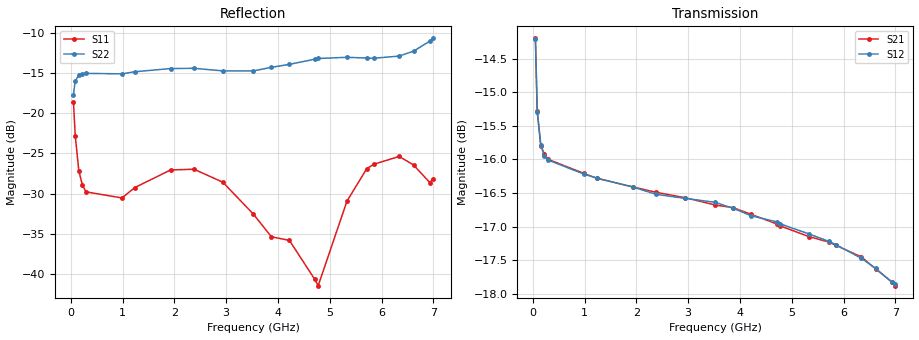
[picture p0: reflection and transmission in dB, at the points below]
! Integrated Device Technology
! Corporate Headquarters
! 6024 Silver Creek Valley Road
! San Jose, CA 95138  USA
! Phone:  1-408-284-8200
! Toll Free:  1-800-223-1366
! Webpage:  http://www.idt.com/
! Timing and RF Division
! 515 Groton Road, Suite 102
! Westford, MA 01886-6024
! Device:  F2258
! Description: Voltage Variable RF Attenuator
! Frequency:  50.0 -  6000.00 MHz
! Package:  3x3 mm Thin QFN Plastic Package: 16 pin
! Ports:  2 RF, 2 DC
!  Pin  1  = NC
!  Pin  2  = NC
!  Pin  3  = RF2  = Port 2
!  Pin  4  = GND
!  Pin  5  = Vdd
!  Pin  6  = NC
!  Pin  7  = VCTRL
!  Pin  8  = NC
!  Pin  9  = GND
!  Pin 10  = RF1  = Port 1
!  Pin 11  = NC
!  Pin 12  = NC
!  Pin 13  = NC
!  Pin 14  = NC
!  Pin 15  = NC
!  Pin 16  = NC
! Vcntrl:  1.210 Volts
! Vdd:  +3.300 Volts
! Current:  1.164 mA
! Data:  The device was measured on a the F2258 evaluation board which has
!  individual transmission lines to the RF pins.  Data was collected
!  using a calibrated network analyzer.  The evaluation board was
!  de-embedded using a TRL calibration technique.
!  The reference plane is the edge of the package pin.
! Misc:  SN 10
!  Action Tracker AT0285
! Date Measured:  2014-12-10
! Date:  2016-01-13  MJV
! Note:
!  Integrated Device Technology supplies this data as a sample of measured
!  data at the package pin for this product.  Your particular data for this
!  product may vary.
!  Data was taken at 25 degrees C.
!  Integrated Device Technology reserves the right to change this data at anytime.
!Freq_(GHz)  S11M_(dB)  S11P_(deg)  S21M_(dB)  S21P_(deg)  S12M_(dB)  S12P_(deg)  S22M_(dB)  S22P_(deg)
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# GHz S dB R 50
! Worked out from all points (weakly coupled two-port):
!   201 points, 50 MHz to 7 GHz, reference 50 ohm
!   highest |S21| = -14.20 dB at 50 MHz (marker M1); lowest = -17.9 dB at 7 GHz (marker M2)
!   lowest |S11| = -41.4 dB at 4.776 GHz (marker M3), VSWR 1.02, Z = 50.6 + j0.614 ohm
!   |S11| at or under -10 dB: start of sweep to end of sweep
!   |S22| runs from -17.7 to -10.7 dB; largest |S21 - S12| = 0.00093
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0.05  -18.60 -95.2  -14.20 -24.0  -14.21 -24.0  -17.72 -23.1
0.08475  -22.81 -81.5  -15.28 -17.1  -15.29 -17.1  -16.01 -12.0
0.15425  -27.19 -61.3  -15.80 -11.8  -15.79 -11.8  -15.31 -9.3
0.22375  -28.96 -47.9  -15.92 -10.1  -15.95 -10.2  -15.14 -9.3
0.29325  -29.79 -37.4  -16.00 -9.8  -16.01 -9.8  -15.07 -10.6
0.98825  -30.55 -19.3  -16.21 -16.7  -16.22 -16.7  -15.13 -28.0
1.2315  -29.27 -14.3  -16.28 -20.0  -16.28 -20.0  -14.87 -33.9
1.9265  -27.07 -3.8  -16.41 -29.7  -16.41 -29.7  -14.47 -50.0
2.37825  -26.98 3.5  -16.49 -36.0  -16.52 -36.0  -14.44 -60.7
2.93425  -28.59 18.2  -16.57 -44.0  -16.58 -44.0  -14.76 -76.5
3.525  -32.56 45.5  -16.68 -52.6  -16.64 -52.7  -14.76 -98.4
3.8725  -35.37 72.2  -16.72 -57.8  -16.73 -57.7  -14.32 -111.4
4.22  -35.82 89.3  -16.82 -62.8  -16.84 -62.7  -13.95 -121.4
4.7065  -40.63 60.0  -16.96 -69.6  -16.93 -69.6  -13.31 -131.7
4.776  -41.45 45.8  -16.99 -70.6  -16.96 -70.7  -13.22 -132.8
5.332  -30.94 -5.5  -17.15 -78.3  -17.11 -78.3  -13.07 -140.0
5.71425  -26.91 -4.1  -17.23 -83.6  -17.22 -83.6  -13.17 -145.8
5.85325  -26.36 -1.4  -17.28 -85.5  -17.27 -85.6  -13.19 -148.9
6.33975  -25.39 11.4  -17.45 -92.4  -17.47 -92.5  -12.92 -161.1
6.61775  -26.45 30.8  -17.63 -96.0  -17.62 -96.0  -12.31 -169.4
6.9305  -28.63 72.6  -17.82 -99.7  -17.83 -99.7  -11.07 -178.3
7  -28.14 87.0  -17.88 -100.4  -17.86 -100.4  -10.72 179.4
